VERSION 5.7 ;
  NOWIREEXTENSIONATPIN ON ;
  DIVIDERCHAR "/" ;
  BUSBITCHARS "[]" ;
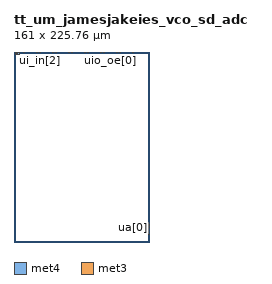
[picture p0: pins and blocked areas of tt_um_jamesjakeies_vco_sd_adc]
MACRO tt_um_jamesjakeies_vco_sd_adc
  CLASS BLOCK ;
  FOREIGN tt_um_jamesjakeies_vco_sd_adc 0.000 0.000 ;
  ORIGIN 0.000 0.000 ;
  SIZE 161.000 BY 225.760 ;
  SYMMETRY X Y ;
  PIN VDPWR
    DIRECTION INOUT ;
    USE POWER ;
    PORT
      LAYER met4 ;
        RECT 1.700 222.760 3.300 224.760 ;
    END
  END VDPWR
  PIN VGND
    DIRECTION INOUT ;
    USE GROUND ;
    PORT
      LAYER met4 ;
        RECT 4.400 222.760 6.000 224.760 ;
    END
  END VGND
  PIN clk
    DIRECTION INPUT ;
    USE SIGNAL ;
    PORT
      LAYER met3 ;
        RECT 11.780 224.760 12.220 225.760 ;
    END
  END clk
  PIN ena
    DIRECTION INPUT ;
    USE SIGNAL ;
    PORT
      LAYER met3 ;
        RECT 19.380 224.760 19.820 225.760 ;
    END
  END ena
  PIN rst_n
    DIRECTION INPUT ;
    USE SIGNAL ;
    PORT
      LAYER met3 ;
        RECT 15.580 224.760 16.020 225.760 ;
    END
  END rst_n
  PIN ua[0]
    DIRECTION INOUT ;
    USE ANALOG ;
    PORT
      LAYER met3 ;
        RECT 160.000 16.780 161.000 17.220 ;
    END
  END ua[0]
  PIN ua[1]
    DIRECTION INOUT ;
    USE ANALOG ;
    PORT
      LAYER met3 ;
        RECT 160.000 19.780 161.000 20.220 ;
    END
  END ua[1]
  PIN ua[2]
    DIRECTION INOUT ;
    USE ANALOG ;
    PORT
      LAYER met3 ;
        RECT 160.000 8.460 161.000 8.900 ;
    END
  END ua[2]
  PIN ui_in[0]
    DIRECTION INPUT ;
    USE SIGNAL ;
    PORT
      LAYER met3 ;
        RECT 23.180 224.760 23.620 225.760 ;
    END
  END ui_in[0]
  PIN ui_in[1]
    DIRECTION INPUT ;
    USE SIGNAL ;
    PORT
      LAYER met3 ;
        RECT 26.980 224.760 27.420 225.760 ;
    END
  END ui_in[1]
  PIN ui_in[2]
    DIRECTION INPUT ;
    USE SIGNAL ;
    PORT
      LAYER met3 ;
        RECT 30.780 224.760 31.220 225.760 ;
    END
  END ui_in[2]
  PIN ui_in[3]
    DIRECTION INPUT ;
    USE SIGNAL ;
    PORT
      LAYER met3 ;
        RECT 34.580 224.760 35.020 225.760 ;
    END
  END ui_in[3]
  PIN ui_in[4]
    DIRECTION INPUT ;
    USE SIGNAL ;
    PORT
      LAYER met3 ;
        RECT 38.380 224.760 38.820 225.760 ;
    END
  END ui_in[4]
  PIN ui_in[5]
    DIRECTION INPUT ;
    USE SIGNAL ;
    PORT
      LAYER met3 ;
        RECT 42.180 224.760 42.620 225.760 ;
    END
  END ui_in[5]
  PIN ui_in[6]
    DIRECTION INPUT ;
    USE SIGNAL ;
    PORT
      LAYER met3 ;
        RECT 45.980 224.760 46.420 225.760 ;
    END
  END ui_in[6]
  PIN ui_in[7]
    DIRECTION INPUT ;
    USE SIGNAL ;
    PORT
      LAYER met3 ;
        RECT 49.780 224.760 50.220 225.760 ;
    END
  END ui_in[7]
  PIN uio_oe[0]
    DIRECTION OUTPUT ;
    USE SIGNAL ;
    PORT
      LAYER met3 ;
        RECT 114.380 224.760 114.820 225.760 ;
    END
  END uio_oe[0]
  PIN uio_oe[1]
    DIRECTION OUTPUT ;
    USE SIGNAL ;
    PORT
      LAYER met3 ;
        RECT 118.180 224.760 118.620 225.760 ;
    END
  END uio_oe[1]
  PIN uio_oe[2]
    DIRECTION OUTPUT ;
    USE SIGNAL ;
    PORT
      LAYER met3 ;
        RECT 121.980 224.760 122.420 225.760 ;
    END
  END uio_oe[2]
  PIN uio_oe[3]
    DIRECTION OUTPUT ;
    USE SIGNAL ;
    PORT
      LAYER met3 ;
        RECT 125.780 224.760 126.220 225.760 ;
    END
  END uio_oe[3]
  PIN uio_oe[4]
    DIRECTION OUTPUT ;
    USE SIGNAL ;
    PORT
      LAYER met3 ;
        RECT 129.580 224.760 130.020 225.760 ;
    END
  END uio_oe[4]
  PIN uio_oe[5]
    DIRECTION OUTPUT ;
    USE SIGNAL ;
    PORT
      LAYER met3 ;
        RECT 133.380 224.760 133.820 225.760 ;
    END
  END uio_oe[5]
  PIN uio_oe[6]
    DIRECTION OUTPUT ;
    USE SIGNAL ;
    PORT
      LAYER met3 ;
        RECT 137.180 224.760 137.620 225.760 ;
    END
  END uio_oe[6]
  PIN uio_oe[7]
    DIRECTION OUTPUT ;
    USE SIGNAL ;
    PORT
      LAYER met3 ;
        RECT 140.980 224.760 141.420 225.760 ;
    END
  END uio_oe[7]
  PIN uio_out[0]
    DIRECTION OUTPUT ;
    USE SIGNAL ;
    PORT
      LAYER met3 ;
        RECT 83.980 224.760 84.420 225.760 ;
    END
  END uio_out[0]
  PIN uio_out[1]
    DIRECTION OUTPUT ;
    USE SIGNAL ;
    PORT
      LAYER met3 ;
        RECT 87.780 224.760 88.220 225.760 ;
    END
  END uio_out[1]
  PIN uio_out[2]
    DIRECTION OUTPUT ;
    USE SIGNAL ;
    PORT
      LAYER met3 ;
        RECT 91.580 224.760 92.020 225.760 ;
    END
  END uio_out[2]
  PIN uio_out[3]
    DIRECTION OUTPUT ;
    USE SIGNAL ;
    PORT
      LAYER met3 ;
        RECT 95.380 224.760 95.820 225.760 ;
    END
  END uio_out[3]
  PIN uio_out[4]
    DIRECTION OUTPUT ;
    USE SIGNAL ;
    PORT
      LAYER met3 ;
        RECT 99.180 224.760 99.620 225.760 ;
    END
  END uio_out[4]
  PIN uio_out[5]
    DIRECTION OUTPUT ;
    USE SIGNAL ;
    PORT
      LAYER met3 ;
        RECT 102.980 224.760 103.420 225.760 ;
    END
  END uio_out[5]
  PIN uio_out[6]
    DIRECTION OUTPUT ;
    USE SIGNAL ;
    PORT
      LAYER met3 ;
        RECT 106.780 224.760 107.220 225.760 ;
    END
  END uio_out[6]
  PIN uio_out[7]
    DIRECTION OUTPUT ;
    USE SIGNAL ;
    PORT
      LAYER met3 ;
        RECT 110.580 224.760 111.020 225.760 ;
    END
  END uio_out[7]
  PIN uo_out[0]
    DIRECTION OUTPUT ;
    USE SIGNAL ;
    PORT
      LAYER met3 ;
        RECT 53.580 224.760 54.020 225.760 ;
    END
  END uo_out[0]
  PIN uo_out[1]
    DIRECTION OUTPUT ;
    USE SIGNAL ;
    PORT
      LAYER met3 ;
        RECT 57.380 224.760 57.820 225.760 ;
    END
  END uo_out[1]
  PIN uo_out[2]
    DIRECTION OUTPUT ;
    USE SIGNAL ;
    PORT
      LAYER met3 ;
        RECT 61.180 224.760 61.620 225.760 ;
    END
  END uo_out[2]
  PIN uo_out[3]
    DIRECTION OUTPUT ;
    USE SIGNAL ;
    PORT
      LAYER met3 ;
        RECT 64.980 224.760 65.420 225.760 ;
    END
  END uo_out[3]
  PIN uo_out[4]
    DIRECTION OUTPUT ;
    USE SIGNAL ;
    PORT
      LAYER met3 ;
        RECT 68.780 224.760 69.220 225.760 ;
    END
  END uo_out[4]
  PIN uo_out[5]
    DIRECTION OUTPUT ;
    USE SIGNAL ;
    PORT
      LAYER met3 ;
        RECT 72.580 224.760 73.020 225.760 ;
    END
  END uo_out[5]
  PIN uo_out[6]
    DIRECTION OUTPUT ;
    USE SIGNAL ;
    PORT
      LAYER met3 ;
        RECT 76.380 224.760 76.820 225.760 ;
    END
  END uo_out[6]
  PIN uo_out[7]
    DIRECTION OUTPUT ;
    USE SIGNAL ;
    PORT
      LAYER met3 ;
        RECT 80.180 224.760 80.620 225.760 ;
    END
  END uo_out[7]
END tt_um_jamesjakeies_vco_sd_adc
END LIBRARY
